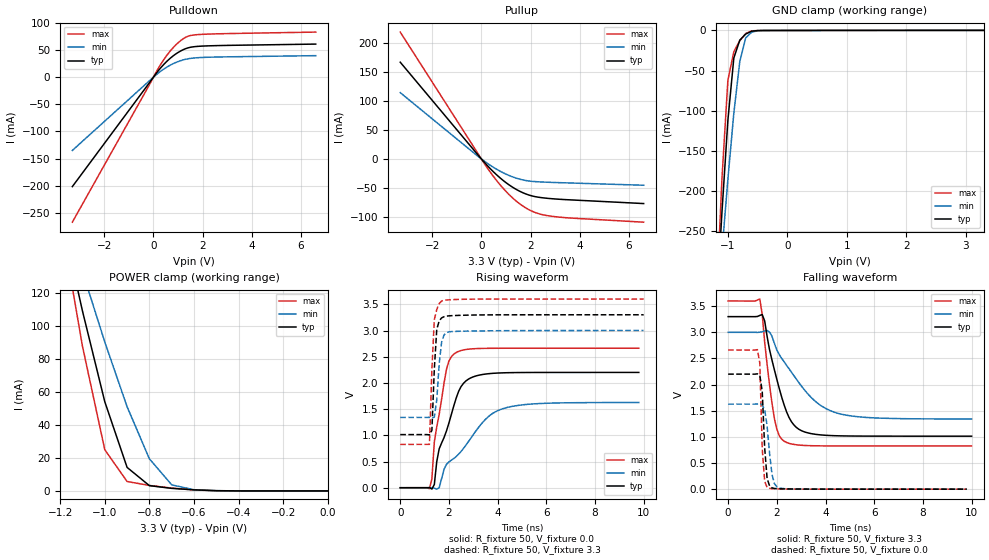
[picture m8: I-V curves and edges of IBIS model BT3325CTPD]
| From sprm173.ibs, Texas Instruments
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[Model]   BT3325CTPD
| I/O with pulldown
Model_type   I/O
Vinh = 2.00
Vinl = 0.80
Enable   Active-Low
Polarity   Non-Inverting
| signals   A, GZ, Y
Vmeas = 1.5
|   typ   min   max
C_comp   1.6130p   1.5354p   1.7989p
|   typ   min   max
[Temperature Range]   25   -40   125
|   typ   min   max
[Voltage Range]   3.30V   3.00V   3.60V
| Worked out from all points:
|   slope of the pulldown table from 0 to 0.495 V, typ, clamps not added: 18.4 ohm
|   slope of the pullup table from 0 to 0.495 V, typ, clamps not added: 22.1 ohm
|   GND clamp passes 1 mA (typ) near -0.60 V on its own axis
|   POWER clamp passes 1 mA (typ) near -0.64 V on its own axis
|   rising waveform, R_fixture 50, V_fixture 0.0: 20-80 % time 850ps typ, 1.71ns min, 498ps max; typ from 0 V to 2.2 V
|   falling waveform, R_fixture 50, V_fixture 3.3: 20-80 % time 776ps typ, 1.6ns min, 434ps max; typ from 3.3 V to 1.01 V
|   rising waveform, R_fixture 50, V_fixture 3.3: 20-80 % time 144ps typ, 173ps min, 144ps max; typ from 1.01 V to 3.3 V
|   falling waveform, R_fixture 50, V_fixture 0.0: 20-80 % time 150ps typ, 219ps min, 121ps max; typ from 2.2 V to 0 V
[Pulldown]
|   Voltage   I(typ)   I(min)   I(max)
-3.3V     -201.5mA   -134.9mA   -267mA
200mV     11.94mA    7.607mA    16.41mA
600mV     31.43mA    19.94mA    43.44mA
800mV     39.06mA    24.71mA    54.18mA
1.1V      47.98mA    30.18mA    66.99mA
1.4V      53.8mA     33.69mA    75.19mA
1.9V      56.88mA    36.01mA    78.53mA
6.6V      60.8mA     39.52mA    82.88mA
[GND_clamp]
|   Voltage   I(typ)   I(min)   I(max)
-3.3V     -3.364A    -2.538A    -4.366A
-1.2V     -355.4mA   -371.5mA   -350.5mA
-1.1V     -227.1mA   -276.6mA   -185.3mA
-1V       -112mA     -185.8mA   -62.16mA
-900mV    -34.3mA    -103.1mA   -26.42mA
-800mV    -12.1mA    -38.8mA    -12.76mA
-700mV    -4.448mA   -9.108mA   -3.783mA
-600mV    -903.9uA   -2.155mA   -502.2uA
-400mV    -40.42uA   -67.44uA   -56.26uA
3.3V      100.8uA    54.24uA    177.3uA
[Pullup]
|   Voltage   I(typ)   I(min)   I(max)
-3.3V     167.1mA    114.5mA    219.1mA
-200mV    10mA       6.709mA    13.35mA
300mV     -14.08mA   -9.224mA   -19.1mA
600mV     -26.64mA   -17.31mA   -36.28mA
900mV     -37.6mA    -24.2mA    -51.46mA
1.2V      -46.92mA   -29.85mA   -64.58mA
1.5V      -54.52mA   -34.2mA    -75.59mA
1.8V      -60.33mA   -37.21mA   -84.42mA
2.1V      -64.3mA    -38.87mA   -91.01mA
2.7V      -68.04mA   -40.24mA   -98mA
3.6V      -70.63mA   -41.51mA   -101.9mA
6.6V      -77.05mA   -45.41mA   -109.2mA
[POWER_clamp]
|   Voltage   I(typ)   I(min)   I(max)
-3.3V     1.575A     1.191A     2.043A
-1.2V     169.6mA    177.7mA    166.3mA
-1.1V     109.1mA    133.1mA    87.77mA
-1V       54.12mA    90.35mA    24.99mA
-900mV    14.26mA    51.09mA    5.719mA
-800mV    3.198mA    19.47mA    3.326mA
-700mV    1.555mA    3.689mA    1.723mA
-600mV    651.9uA    701.7uA    604.8uA
-400mV    15.1uA     22.01uA    4.72uA
0V        399.7pA    10.48nA    133.2pA
[Ramp]
|   I(typ)   I(min)   I(max)
dV/dt_r   1.320/0.848n   0.976/1.713n   1.597/0.501n
dV/dt_f   1.372/0.780n   0.995/1.605n   1.664/0.436n
[Rising Waveform]
R_fixture = 50
V_fixture = 0.0
|  pu_on
|  TIME   V(typ)   V(min)   V(max)
0s        2nV        12nV       1nV
1.2ns     2.157mV    1.087mV    -18.72mV
1.3ns     -25.42mV   1.598mV    167.7mV
1.4ns     61.1mV     -9.151mV   872.5mV
1.6ns     742.6mV    -1.403mV   1.4V
1.9ns     1.084V     446.9mV    2.261V
2.3ns     1.713V     595.2mV    2.581V
2.9ns     2.097V     945.3mV    2.649V
4.3ns     2.193V     1.52V      2.662V
9.8ns     2.2V       1.626V     2.662V
[Falling Waveform]
R_fixture = 50
V_fixture = 3.3
V_fixture_min = 3.0
V_fixture_max = 3.6
|  pd_on
|  TIME   V(typ)   V(min)   V(max)
0s        3.3V       3V         3.6V
1.3ns     3.323V     3.002V     3.636V
1.4ns     3.339V     3.011V     3.342V
1.5ns     3.218V     3.025V     2.812V
1.9ns     2.282V     2.788V     1.351V
2.1ns     1.924V     2.573V     1.022V
2.3ns     1.61V      2.434V     917.4mV
2.9ns     1.147V     2.041V     843.6mV
4.4ns     1.022V     1.466V     826.9mV
10ns      1.014V     1.342V     826.4mV
[Rising Waveform]
R_fixture = 50
V_fixture = 3.3
V_fixture_min = 3.0
V_fixture_max = 3.6
|  pd_off
|  TIME   V(typ)   V(min)   V(max)
0s        1.014V     1.342V     826.4mV
1.2ns     1.007V     1.343V     827.5mV
1.3ns     1.093V     1.327V     2.255V
1.4ns     2.263V     1.349V     3.205V
1.5ns     3.021V     1.672V     3.399V
1.6ns     3.184V     2.37V      3.514V
1.7ns     3.241V     2.78V      3.563V
1.8ns     3.263V     2.915V     3.577V
2.1ns     3.283V     2.979V     3.588V
10ns      3.3V       3V         3.6V
[Falling Waveform]
R_fixture = 50
V_fixture = 0.0
|  pu_off
|  TIME   V(typ)   V(min)   V(max)
0s        2.2V       1.626V     2.662V
1.2ns     2.206V     1.629V     2.668V
1.3ns     2.178V     1.634V     2.417V
1.4ns     1.865V     1.612V     776.7mV
1.5ns     790.7mV    1.521V     148.6mV
1.6ns     205mV      1.209V     34.17mV
1.8ns     25.87mV    284.3mV    9.32mV
1.9ns     13.53mV    107.5mV    7.244mV
2.1ns     7.396mV    24.01mV    4.838mV
9.8ns     1.786uV    6.55uV     476nV
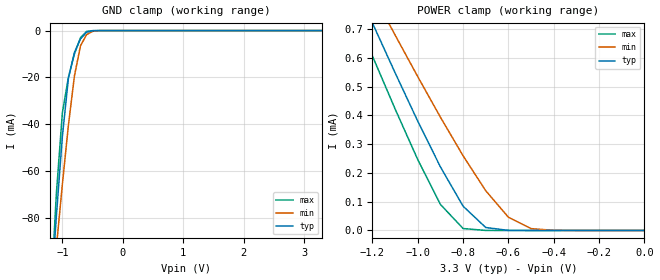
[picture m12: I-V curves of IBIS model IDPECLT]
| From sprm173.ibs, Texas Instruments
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[Model]   IDPECLT
| differential input
Model_type   Input
Polarity   Non-Inverting
| signals   A, AN, Y
Vinl = 0.8V
Vinh = 2.0V
|   typ   min   max
C_comp   1.4205p   1.4132p   1.4238p
|   typ   min   max
[Temperature Range]   25   -40   125
|   typ   min   max
[Voltage Range]   3.30V   3.00V   3.60V
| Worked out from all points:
|   GND clamp passes 1 mA (typ) near -0.61 V on its own axis
|   POWER clamp passes 1 mA (typ) near -1.36 V on its own axis
[GND_clamp]
|   Voltage   I(typ)   I(min)   I(max)
-3.3V     -1.003A    -759.2mA   -1.299A
-1.2V     -117.2mA   -120.9mA   -117.6mA
-1.1V     -79.39mA   -92.69mA   -69.82mA
-1V       -45.17mA   -65.55mA   -35.06mA
-900mV    -20.34mA   -40.38mA   -19.94mA
-800mV    -9.299mA   -19.3mA    -9.961mA
-700mV    -3.571mA   -6.474mA   -3.043mA
-600mV    -721.8uA   -1.751mA   -360.8uA
-500mV    -67.09uA   -324uA     -17.01uA
-400mV    -3.755uA   -40.26uA   -379.8nA
3.3V      222pA      31.75nA    -88.82pA
[POWER_clamp]
|   Voltage   I(typ)   I(min)   I(max)
-3.3V     4.554mA    4.066mA    4.702mA
-1.3V     896.5uA    975.2uA    793.5uA
-1.2V     720.7uA    826.3uA    605.9uA
-1.1V     547.8uA    679uA      422.1uA
-1V       379.7uA    534.4uA    246.1uA
-900mV    220.8uA    393.6uA    90.43uA
-800mV    84.27uA    259.4uA    6.778uA
-700mV    10.28uA    138.1uA    73.63nA
-600mV    329.6nA    45.87uA    710.5pA
-500mV    8.393nA    6.454uA    88.82pA
-400mV    355.3pA    466.6nA    0A
0V        133.2pA    2.398nA    88.82pA
